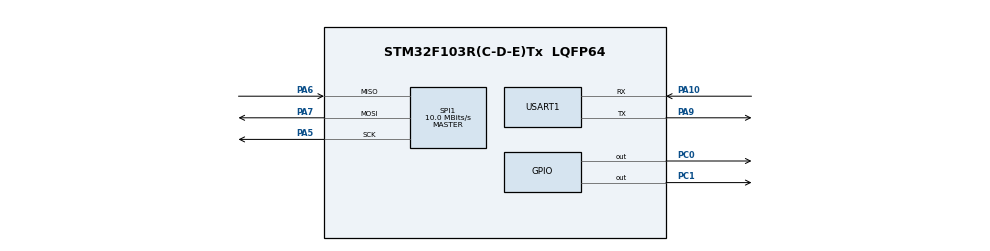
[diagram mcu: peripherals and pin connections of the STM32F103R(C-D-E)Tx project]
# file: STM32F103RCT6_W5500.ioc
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Mcu.Family=STM32F1
Mcu.Name=STM32F103R(C-D-E)Tx
Mcu.Package=LQFP64
NVIC.PriorityGroup=NVIC_PRIORITYGROUP_4
PA10.Mode=Asynchronous
PA10.Signal=USART1_RX
PA5.Mode=Full_Duplex_Master
PA5.Signal=SPI1_SCK
PA6.Mode=Full_Duplex_Master
PA6.Signal=SPI1_MISO
PA7.Mode=Full_Duplex_Master
PA7.Signal=SPI1_MOSI
PA9.Mode=Asynchronous
PA9.Signal=USART1_TX
PC0.Signal=GPIO_Output
PC1.Signal=GPIO_Output
ProjectManager.HeapSize=0x200
ProjectManager.StackSize=0x400
ProjectManager.TargetToolchain=STM32CubeIDE
RCC.AHBFreq_Value=20000000
RCC.APB1Freq_Value=20000000
RCC.APB1TimFreq_Value=20000000
RCC.APB2Freq_Value=20000000
RCC.APB2TimFreq_Value=20000000
RCC.HCLKFreq_Value=20000000
RCC.PLLMUL=RCC_PLL_MUL5
RCC.SYSCLKFreq_VALUE=20000000
RCC.SYSCLKSource=RCC_SYSCLKSOURCE_PLLCLK
RCC.USBFreq_Value=20000000
SPI1.BaudRatePrescaler=SPI_BAUDRATEPRESCALER_2
SPI1.CalculateBaudRate=10.0 MBits/s
SPI1.Direction=SPI_DIRECTION_2LINES
SPI1.Mode=SPI_MODE_MASTER
SPI1.VirtualType=VM_MASTER
USART1.VirtualMode=VM_ASYNC
VP_SYS_VS_ND.Mode=No_Debug
board=custom

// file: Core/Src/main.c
/* USER CODE BEGIN Header */
/**
  ******************************************************************************
  * @file           : main.c
  * @brief          : Main program body
  ******************************************************************************
  * @attention
  *
  * <h2><center>&copy; Copyright (c) 2020 STMicroelectronics.
  * All rights reserved.</center></h2>
  *
  * This software component is licensed by ST under BSD 3-Clause license,
  * the "License"; You may not use this file except in compliance with the
  * License. You may obtain a copy of the License at:
  *                        opensource.org/licenses/BSD-3-Clause
  *
  ******************************************************************************
  */
#include "main.h"

#include <string.h>
#include <stdarg.h>
#include <stdbool.h>
#include <ctype.h>
#include "socket.h"
#include "dhcp.h"
#include "dns.h"

#define DHCP_SOCKET     0
#define DNS_SOCKET      1
#define HTTP_SOCKET     2

#define W5500_CS_PIN 	GPIO_PIN_2
#define W5500_CS_PORT 	GPIOB
#define ULED_PIN 		GPIO_PIN_2
#define ULED_GPIO_PORT 	GPIOD
/* USER CODE BEGIN PM */
// 1K should be enough, see https://forum.wiznet.io/t/topic/1612/2
uint8_t dhcp_buffer[1024];
// 1K seems to be enough for this buffer as well
uint8_t dns_buffer[1024];
/* USER CODE END PM */

SPI_HandleTypeDef hspi1;

UART_HandleTypeDef huart1;

void SystemClock_Config(void);
static void MX_GPIO_Init(void);
static void MX_SPI1_Init(void);
static void MX_USART1_UART_Init(void);

void UART_Printf(const char* fmt, ...) {
    char buff[256];
    va_list args;
    va_start(args, fmt);
    //vsnprintf(buff, sizeof(buff), fmt, args);
    HAL_UART_Transmit(&huart1, (uint8_t*)buff, strlen(buff),
                      HAL_MAX_DELAY);
    va_end(args);
}

void W5500_Select(void) {
    HAL_GPIO_WritePin(W5500_CS_PORT, W5500_CS_PIN, GPIO_PIN_RESET);
}

void W5500_Unselect(void) {
    HAL_GPIO_WritePin(W5500_CS_PORT, W5500_CS_PIN, GPIO_PIN_SET);
}

void W5500_ReadBuff(uint8_t* buff, uint16_t len) {
    HAL_SPI_Receive(&hspi1, buff, len, HAL_MAX_DELAY);
}

void W5500_WriteBuff(uint8_t* buff, uint16_t len) {
    HAL_SPI_Transmit(&hspi1, buff, len, HAL_MAX_DELAY);
}

uint8_t W5500_ReadByte(void) {
    uint8_t byte;
    W5500_ReadBuff(&byte, sizeof(byte));
    return byte;
}

void W5500_WriteByte(uint8_t byte) {
    W5500_WriteBuff(&byte, sizeof(byte));
}

volatile bool ip_assigned = false;

void Callback_IPAssigned(void) {
    UART_Printf("Callback: IP assigned! Leased time: %d sec\r\n", getDHCPLeasetime());
    ip_assigned = true;
}

void Callback_IPConflict(void) {
    UART_Printf("Callback: IP conflict!\r\n");
}
/*******************************************************************/
void init()
{
    UART_Printf("\r\ninit() called!\r\n");
    UART_Printf("Registering W5500 callbacks...\r\n");
    reg_wizchip_cs_cbfunc(W5500_Select, W5500_Unselect);
    reg_wizchip_spi_cbfunc(W5500_ReadByte, W5500_WriteByte);
    reg_wizchip_spiburst_cbfunc(W5500_ReadBuff, W5500_WriteBuff);

    UART_Printf("Calling wizchip_init()...\r\n");
    uint8_t rx_tx_buff_sizes[] = {2, 2, 2, 2, 2, 2, 2, 2};
    wizchip_init(rx_tx_buff_sizes, rx_tx_buff_sizes);

    UART_Printf("Calling DHCP_init()...\r\n");
    wiz_NetInfo net_info = {
        .mac  = { 0xEA, 0x11, 0x22, 0x33, 0x44, 0xEA },
        .dhcp = NETINFO_DHCP
    };
    // set MAC address before using DHCP
    setSHAR(net_info.mac);
    DHCP_init(DHCP_SOCKET, dhcp_buffer);

    UART_Printf("Registering DHCP callbacks...\r\n");
    reg_dhcp_cbfunc(
        Callback_IPAssigned,
        Callback_IPAssigned,
        Callback_IPConflict
    );

    UART_Printf("Calling DHCP_run()...\r\n");
    // actually should be called in a loop, e.g. by timer
    uint32_t ctr = 10000;
    while((!ip_assigned) && (ctr > 0)) {
        DHCP_run();
        ctr--;
    }
    if(!ip_assigned) {
        UART_Printf("\r\nIP was not assigned :(\r\n");
        return;
    }

    getIPfromDHCP(net_info.ip);
    getGWfromDHCP(net_info.gw);
    getSNfromDHCP(net_info.sn);

    uint8_t dns[4];
    getDNSfromDHCP(dns);

    UART_Printf("IP:  %d.%d.%d.%d\r\nGW:  %d.%d.%d.%d\r\nNet: %d.%d.%d.%d\r\nDNS: %d.%d.%d.%d\r\n",
        net_info.ip[0], net_info.ip[1], net_info.ip[2], net_info.ip[3],
        net_info.gw[0], net_info.gw[1], net_info.gw[2], net_info.gw[3],
        net_info.sn[0], net_info.sn[1], net_info.sn[2], net_info.sn[3],
        dns[0], dns[1], dns[2], dns[3]
    );

    UART_Printf("Calling wizchip_setnetinfo()...\r\n");
    wizchip_setnetinfo(&net_info);

    UART_Printf("Calling DNS_init()...\r\n");
    DNS_init(DNS_SOCKET, dns_buffer);

    uint8_t addr[4];
    {
        char domain_name[] = "eax.me";
        UART_Printf("Resolving domain name \"%s\"...\r\n", domain_name);
        int8_t res = DNS_run(dns, (uint8_t*)&domain_name, addr);
        if(res != 1) {
            UART_Printf("DNS_run() failed, res = %d", res);
            return;
        }
        UART_Printf("Result: %d.%d.%d.%d\r\n", addr[0], addr[1], addr[2], addr[3]);
    }

    UART_Printf("Creating socket...\r\n");
    uint8_t http_socket = HTTP_SOCKET;
    uint8_t code = socket(http_socket, Sn_MR_TCP, 10888, 0);
    if(code != http_socket) {
        UART_Printf("socket() failed, code = %d\r\n", code);
        return;
    }

    UART_Printf("Socket created, connecting...\r\n");
    code = connect(http_socket, addr, 80);
    if(code != SOCK_OK) {
        UART_Printf("connect() failed, code = %d\r\n", code);
        close(http_socket);
        return;
    }

    UART_Printf("Connected, sending HTTP request...\r\n");
    {
        char req[] = "GET / HTTP/1.0\r\nHost: eax.me\r\n\r\n";
        uint16_t len = sizeof(req) - 1;
        uint8_t* buff = (uint8_t*)&req;
        while(len > 0) {
            UART_Printf("Sending %d bytes...\r\n", len);
            int32_t nbytes = send(http_socket, buff, len);
            if(nbytes <= 0) {
                UART_Printf("send() failed, %d returned\r\n", nbytes);
                close(http_socket);
                return;
            }
            UART_Printf("%d bytes sent!\r\n", nbytes);
            len -= nbytes;
        }
    }

    UART_Printf("Request sent. Reading response...\r\n");
    {
        char buff[32];
        for(;;) {
            int32_t nbytes = recv(http_socket, (uint8_t*)&buff, sizeof(buff)-1);
            if(nbytes == SOCKERR_SOCKSTATUS) {
                UART_Printf("\r\nConnection closed.\r\n");
                break;
            }

            if(nbytes <= 0) {
                UART_Printf("\r\nrecv() failed, %d returned\r\n", nbytes);
                break;
            }

            buff[nbytes] = '\0';
            UART_Printf("%s", buff);
        }
    }

    UART_Printf("Closing socket.\r\n");
    close(http_socket);
}
/*******************************************************************/
int main(void)
{
	HAL_Init();
	SystemClock_Config();
	MX_GPIO_Init();
	MX_SPI1_Init();
	MX_USART1_UART_Init();
	init();
	while (1)
	{
		HAL_GPIO_TogglePin(GPIOC, GPIO_PIN_0);
		HAL_Delay(200);
	}
}
/*******************************************************************/
void SystemClock_Config(void)
{
	RCC_OscInitTypeDef RCC_OscInitStruct = {0};
	RCC_ClkInitTypeDef RCC_ClkInitStruct = {0};

	RCC_OscInitStruct.OscillatorType = RCC_OSCILLATORTYPE_HSI;
	RCC_OscInitStruct.HSIState = RCC_HSI_ON;
	RCC_OscInitStruct.HSICalibrationValue = RCC_HSICALIBRATION_DEFAULT;
	RCC_OscInitStruct.PLL.PLLState = RCC_PLL_ON;
	RCC_OscInitStruct.PLL.PLLSource = RCC_PLLSOURCE_HSI_DIV2;
	RCC_OscInitStruct.PLL.PLLMUL = RCC_PLL_MUL8;
	if (HAL_RCC_OscConfig(&RCC_OscInitStruct) != HAL_OK)
	{
		Error_Handler();
	}
	RCC_ClkInitStruct.ClockType = RCC_CLOCKTYPE_HCLK|RCC_CLOCKTYPE_SYSCLK
							  |RCC_CLOCKTYPE_PCLK1|RCC_CLOCKTYPE_PCLK2;
	RCC_ClkInitStruct.SYSCLKSource = RCC_SYSCLKSOURCE_PLLCLK;
	RCC_ClkInitStruct.AHBCLKDivider = RCC_SYSCLK_DIV1;
	RCC_ClkInitStruct.APB1CLKDivider = RCC_HCLK_DIV1;
	RCC_ClkInitStruct.APB2CLKDivider = RCC_HCLK_DIV1;

	if (HAL_RCC_ClockConfig(&RCC_ClkInitStruct, FLASH_LATENCY_0) != HAL_OK)
	{
		Error_Handler();
	}
}
/*******************************************************************/
static void MX_SPI1_Init(void)
{
	hspi1.Instance = SPI1;
	hspi1.Init.Mode = SPI_MODE_MASTER;
	hspi1.Init.Direction = SPI_DIRECTION_2LINES;
	hspi1.Init.DataSize = SPI_DATASIZE_8BIT;
	hspi1.Init.CLKPolarity = SPI_POLARITY_LOW;
	hspi1.Init.CLKPhase = SPI_PHASE_1EDGE;
	hspi1.Init.NSS = SPI_NSS_SOFT;
	hspi1.Init.BaudRatePrescaler = SPI_BAUDRATEPRESCALER_2;
	hspi1.Init.FirstBit = SPI_FIRSTBIT_MSB;
	hspi1.Init.TIMode = SPI_TIMODE_DISABLE;
	hspi1.Init.CRCCalculation = SPI_CRCCALCULATION_DISABLE;
	hspi1.Init.CRCPolynomial = 10;
	if (HAL_SPI_Init(&hspi1) != HAL_OK)
	{
		Error_Handler();
	}
}
/*******************************************************************/
static void MX_USART1_UART_Init(void)
{
	huart1.Instance = USART1;
	huart1.Init.BaudRate = 115200;
	huart1.Init.WordLength = UART_WORDLENGTH_8B;
	huart1.Init.StopBits = UART_STOPBITS_1;
	huart1.Init.Parity = UART_PARITY_NONE;
	huart1.Init.Mode = UART_MODE_TX_RX;
	huart1.Init.HwFlowCtl = UART_HWCONTROL_NONE;
	huart1.Init.OverSampling = UART_OVERSAMPLING_16;
	if (HAL_UART_Init(&huart1) != HAL_OK)
	{
		Error_Handler();
	}
}
/*******************************************************************/
static void MX_GPIO_Init(void)
{
	GPIO_InitTypeDef GPIO_InitStruct = {0};

	/* GPIO Ports Clock Enable */
	__HAL_RCC_GPIOB_CLK_ENABLE();
	__HAL_RCC_GPIOA_CLK_ENABLE();
	__HAL_RCC_GPIOC_CLK_ENABLE();

	/*Configure GPIO pin Output Level */
	HAL_GPIO_WritePin(GPIOB, GPIO_PIN_2, GPIO_PIN_RESET);
	HAL_GPIO_WritePin(GPIOC, GPIO_PIN_0, GPIO_PIN_RESET);

	/*Configure GPIO pins : PB2 */
	GPIO_InitStruct.Pin = GPIO_PIN_2;
	GPIO_InitStruct.Mode = GPIO_MODE_OUTPUT_PP;
	GPIO_InitStruct.Pull = GPIO_NOPULL;
	GPIO_InitStruct.Speed = GPIO_SPEED_FREQ_LOW;
	HAL_GPIO_Init(GPIOB, &GPIO_InitStruct);

	/*Configure GPIO pins : PC0 */
	GPIO_InitStruct.Pin = GPIO_PIN_0;
	GPIO_InitStruct.Mode = GPIO_MODE_OUTPUT_PP;
	GPIO_InitStruct.Pull = GPIO_NOPULL;
	GPIO_InitStruct.Speed = GPIO_SPEED_FREQ_LOW;
	HAL_GPIO_Init(GPIOC, &GPIO_InitStruct);

}
/*******************************************************************/
void Error_Handler(void)
{
}
/************************ (C) COPYRIGHT STMicroelectronics *****END OF FILE****/
